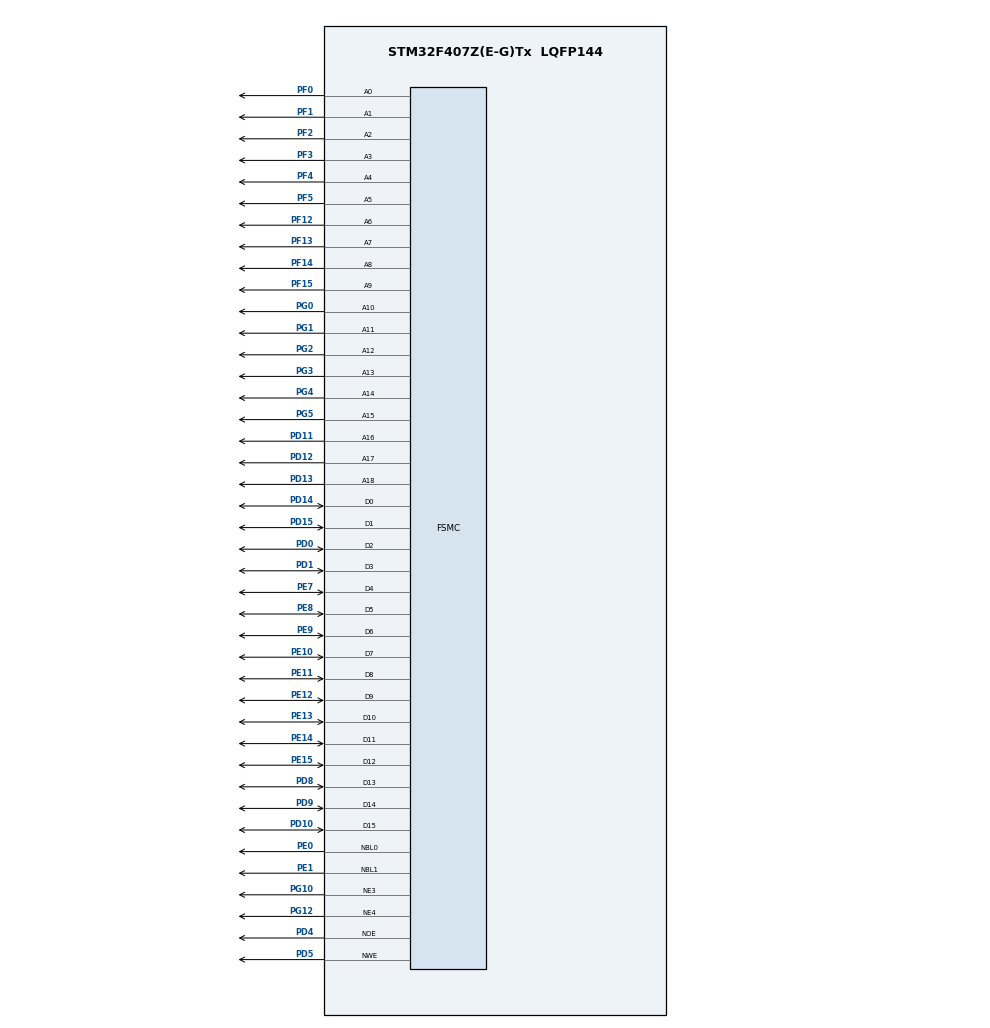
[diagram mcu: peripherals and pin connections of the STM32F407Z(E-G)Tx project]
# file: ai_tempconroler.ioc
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FREERTOS.Tasks01=defaultTask,0,128,StartDefaultTask,Default,NULL,Dynamic,NULL,NULL
FSMC.ExtendedMode1=FSMC_EXTENDED_MODE_DISABLE
FSMC.WriteOperation1=FSMC_WRITE_OPERATION_DISABLE
Mcu.Family=STM32F4
Mcu.Name=STM32F407Z(E-G)Tx
Mcu.Package=LQFP144
NVIC.PriorityGroup=NVIC_PRIORITYGROUP_4
NVIC.TIM1_UP_TIM10_IRQn=true\:15\:0\:false\:false\:true\:false\:false\:true\:true
NVIC.TimeBase=TIM1_UP_TIM10_IRQn
NVIC.TimeBaseIP=TIM1
PC14-OSC32_IN.Mode=LSE-External-Oscillator
PC14-OSC32_IN.Signal=RCC_OSC32_IN
PC15-OSC32_OUT.Mode=LSE-External-Oscillator
PC15-OSC32_OUT.Signal=RCC_OSC32_OUT
PD0.Signal=FSMC_D2_DA2
PD1.Signal=FSMC_D3_DA3
PD10.Signal=FSMC_D15_DA15
PD11.Signal=FSMC_A16_CLE
PD12.Signal=FSMC_A17_ALE
PD13.Signal=FSMC_A18
PD14.Signal=FSMC_D0_DA0
PD15.Signal=FSMC_D1_DA1
PD4.Signal=FSMC_NOE
PD5.Signal=FSMC_NWE
PD8.Signal=FSMC_D13_DA13
PD9.Signal=FSMC_D14_DA14
PE0.Signal=FSMC_NBL0
PE1.Signal=FSMC_NBL1
PE10.Signal=FSMC_D7_DA7
PE11.Signal=FSMC_D8_DA8
PE12.Signal=FSMC_D9_DA9
PE13.Signal=FSMC_D10_DA10
PE14.Signal=FSMC_D11_DA11
PE15.Signal=FSMC_D12_DA12
PE7.Signal=FSMC_D4_DA4
PE8.Signal=FSMC_D5_DA5
PE9.Signal=FSMC_D6_DA6
PF0.Signal=FSMC_A0
PF1.Signal=FSMC_A1
PF12.Signal=FSMC_A6
PF13.Signal=FSMC_A7
PF14.Signal=FSMC_A8
PF15.Signal=FSMC_A9
PF2.Signal=FSMC_A2
PF3.Signal=FSMC_A3
PF4.Signal=FSMC_A4
PF5.Signal=FSMC_A5
PG0.Signal=FSMC_A10
PG1.Signal=FSMC_A11
PG10.Mode=NorPsramChipSelect3_1
PG10.Signal=FSMC_NE3
PG12.Mode=NorPsramChipSelect4_2
PG12.Signal=FSMC_NE4
PG2.Signal=FSMC_A12
PG3.Signal=FSMC_A13
PG4.Signal=FSMC_A14
PG5.Signal=FSMC_A15
PH0-OSC_IN.Mode=HSE-External-Oscillator
PH0-OSC_IN.Signal=RCC_OSC_IN
PH1-OSC_OUT.Mode=HSE-External-Oscillator
PH1-OSC_OUT.Signal=RCC_OSC_OUT
ProjectManager.HeapSize=0x200
ProjectManager.StackSize=0x400
ProjectManager.TargetToolchain=MDK-ARM V5.32
RCC.48MHZClocksFreq_Value=84000000
RCC.AHBFreq_Value=168000000
RCC.APB1CLKDivider=RCC_HCLK_DIV4
RCC.APB1Freq_Value=42000000
RCC.APB1TimFreq_Value=84000000
RCC.APB2CLKDivider=RCC_HCLK_DIV2
RCC.APB2Freq_Value=84000000
RCC.APB2TimFreq_Value=168000000
RCC.CortexFreq_Value=168000000
RCC.HCLKFreq_Value=168000000
RCC.HSE_VALUE=25000000
RCC.HSI_VALUE=16000000
RCC.PLLM=8
RCC.PLLN=168
RCC.SYSCLKFreq_VALUE=168000000
RCC.SYSCLKSource=RCC_SYSCLKSOURCE_PLLCLK
RCC.VCOOutputFreq_Value=336000000
SH.FSMC_A0.0=FSMC_A0,19b-a1
SH.FSMC_A1.0=FSMC_A1,19b-a1
SH.FSMC_A10.0=FSMC_A10,19b-a1
SH.FSMC_A11.0=FSMC_A11,19b-a1
SH.FSMC_A12.0=FSMC_A12,19b-a1
SH.FSMC_A12.1=FSMC_A12,A12_2
SH.FSMC_A13.0=FSMC_A13,19b-a1
SH.FSMC_A14.0=FSMC_A14,19b-a1
SH.FSMC_A15.0=FSMC_A15,19b-a1
SH.FSMC_A16_CLE.0=FSMC_A16,19b-a1
SH.FSMC_A17_ALE.0=FSMC_A17,19b-a1
SH.FSMC_A18.0=FSMC_A18,19b-a1
SH.FSMC_A2.0=FSMC_A2,19b-a1
SH.FSMC_A3.0=FSMC_A3,19b-a1
SH.FSMC_A4.0=FSMC_A4,19b-a1
SH.FSMC_A5.0=FSMC_A5,19b-a1
SH.FSMC_A6.0=FSMC_A6,19b-a1
SH.FSMC_A7.0=FSMC_A7,19b-a1
SH.FSMC_A8.0=FSMC_A8,19b-a1
SH.FSMC_A9.0=FSMC_A9,19b-a1
SH.FSMC_D0_DA0.0=FSMC_D0,16b-d1
SH.FSMC_D0_DA0.1=FSMC_D0,16b-d2
SH.FSMC_D10_DA10.0=FSMC_D10,16b-d1
SH.FSMC_D10_DA10.1=FSMC_D10,16b-d2
SH.FSMC_D11_DA11.0=FSMC_D11,16b-d1
SH.FSMC_D11_DA11.1=FSMC_D11,16b-d2
SH.FSMC_D12_DA12.0=FSMC_D12,16b-d1
SH.FSMC_D12_DA12.1=FSMC_D12,16b-d2
SH.FSMC_D13_DA13.0=FSMC_D13,16b-d1
SH.FSMC_D13_DA13.1=FSMC_D13,16b-d2
SH.FSMC_D14_DA14.0=FSMC_D14,16b-d1
SH.FSMC_D14_DA14.1=FSMC_D14,16b-d2
SH.FSMC_D15_DA15.0=FSMC_D15,16b-d1
SH.FSMC_D15_DA15.1=FSMC_D15,16b-d2
SH.FSMC_D1_DA1.0=FSMC_D1,16b-d1
SH.FSMC_D1_DA1.1=FSMC_D1,16b-d2
SH.FSMC_D2_DA2.0=FSMC_D2,16b-d1
SH.FSMC_D2_DA2.1=FSMC_D2,16b-d2
SH.FSMC_D3_DA3.0=FSMC_D3,16b-d1
SH.FSMC_D3_DA3.1=FSMC_D3,16b-d2
SH.FSMC_D4_DA4.0=FSMC_D4,16b-d1
SH.FSMC_D4_DA4.1=FSMC_D4,16b-d2
SH.FSMC_D5_DA5.0=FSMC_D5,16b-d1
SH.FSMC_D5_DA5.1=FSMC_D5,16b-d2
SH.FSMC_D6_DA6.0=FSMC_D6,16b-d1
SH.FSMC_D6_DA6.1=FSMC_D6,16b-d2
SH.FSMC_D7_DA7.0=FSMC_D7,16b-d1
SH.FSMC_D7_DA7.1=FSMC_D7,16b-d2
SH.FSMC_D8_DA8.0=FSMC_D8,16b-d1
SH.FSMC_D8_DA8.1=FSMC_D8,16b-d2
SH.FSMC_D9_DA9.0=FSMC_D9,16b-d1
SH.FSMC_D9_DA9.1=FSMC_D9,16b-d2
SH.FSMC_NBL0.0=FSMC_NBL0,2ByteEnable1
SH.FSMC_NBL1.0=FSMC_NBL1,2ByteEnable1
SH.FSMC_NOE.0=FSMC_NOE,Sram1
SH.FSMC_NOE.1=FSMC_NOE,Lcd2
SH.FSMC_NWE.0=FSMC_NWE,Sram1
SH.FSMC_NWE.1=FSMC_NWE,Lcd2
VP_FATFS_VS_SRAM.Mode=SRAM
VP_FREERTOS_VS_CMSIS_V1.Mode=CMSIS_V1
VP_LIBJPEG_VS_JPEGLIB.Mode=Enabled
VP_SYS_VS_tim1.Mode=TIM1
board=custom

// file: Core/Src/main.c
/* USER CODE BEGIN Header */
/**
  ******************************************************************************
  * @file           : main.c
  * @brief          : Main program body
  ******************************************************************************
  * @attention
  *
  * Copyright (c) 2026 STMicroelectronics.
  * All rights reserved.
  *
  * This software is licensed under terms that can be found in the LICENSE file
  * in the root directory of this software component.
  * If no LICENSE file comes with this software, it is provided AS-IS.
  *
  ******************************************************************************
  */
/* USER CODE END Header */
#include "main.h"
#include "cmsis_os.h"
#include "fatfs.h"
#include "libjpeg.h"
#include "gpio.h"
#include "fsmc.h"

/* USER CODE BEGIN Includes */
#ifdef ILI9341_SELF_TEST
#include "../../Tests/BSP/ili9341_self_test.h"
#endif
#ifdef LVGL_MINI_TEST
#include "../../Tests/LVGL/lvgl_mini_test.h"
#endif
#include "lvgl.h"
/* USER CODE END Includes */

/* USER CODE BEGIN PV */
extern volatile uint32_t g_boot_stage;

/* USER CODE END PV */

void SystemClock_Config(void);
void MX_FREERTOS_Init(void);

int main(void)
{

  /* MCU Configuration--------------------------------------------------------*/

  /* Reset of all peripherals, Initializes the Flash interface and the Systick. */
  HAL_Init();

  /* Configure the system clock */
  SystemClock_Config();

  /* Initialize all configured peripherals */
  MX_GPIO_Init();
  MX_FSMC_Init();
  MX_FATFS_Init();
  MX_LIBJPEG_Init();
  /* USER CODE BEGIN 2 */
#ifdef ILI9341_SELF_TEST
  ili9341_self_test();
#endif
#ifdef LVGL_MINI_TEST
	lvgl_mini_test();
#endif
  /* USER CODE END 2 */

  /* Call init function for freertos objects (in cmsis_os2.c) */
  MX_FREERTOS_Init();
  g_boot_stage = 0x10U;

  /* Start scheduler */
  osKernelStart();
  g_boot_stage = 0x11U;

  /* We should never get here as control is now taken by the scheduler */

  /* Infinite loop */
  while (1)
  {

  }
}

void SystemClock_Config(void)
{
  RCC_OscInitTypeDef RCC_OscInitStruct = {0};
  RCC_ClkInitTypeDef RCC_ClkInitStruct = {0};

  /** Configure the main internal regulator output voltage
  */
  __HAL_RCC_PWR_CLK_ENABLE();
  __HAL_PWR_VOLTAGESCALING_CONFIG(PWR_REGULATOR_VOLTAGE_SCALE1);

  /** Initializes the RCC Oscillators according to the specified parameters
  * in the RCC_OscInitTypeDef structure.
  */
  RCC_OscInitStruct.OscillatorType = RCC_OSCILLATORTYPE_HSE;
  RCC_OscInitStruct.HSEState = RCC_HSE_ON;
  RCC_OscInitStruct.PLL.PLLState = RCC_PLL_ON;
  RCC_OscInitStruct.PLL.PLLSource = RCC_PLLSOURCE_HSE;
  RCC_OscInitStruct.PLL.PLLM = 8;
  RCC_OscInitStruct.PLL.PLLN = 336;
  RCC_OscInitStruct.PLL.PLLP = RCC_PLLP_DIV2;
  RCC_OscInitStruct.PLL.PLLQ = 7;
  if (HAL_RCC_OscConfig(&RCC_OscInitStruct) != HAL_OK)
  {
    Error_Handler();
  }

  /** Initializes the CPU, AHB and APB buses clocks
  */
  RCC_ClkInitStruct.ClockType = RCC_CLOCKTYPE_HCLK|RCC_CLOCKTYPE_SYSCLK
                              |RCC_CLOCKTYPE_PCLK1|RCC_CLOCKTYPE_PCLK2;
  RCC_ClkInitStruct.SYSCLKSource = RCC_SYSCLKSOURCE_PLLCLK;
  RCC_ClkInitStruct.AHBCLKDivider = RCC_SYSCLK_DIV1;
  RCC_ClkInitStruct.APB1CLKDivider = RCC_HCLK_DIV4;
  RCC_ClkInitStruct.APB2CLKDivider = RCC_HCLK_DIV2;

  if (HAL_RCC_ClockConfig(&RCC_ClkInitStruct, FLASH_LATENCY_5) != HAL_OK)
  {
    Error_Handler();
  }
}

void HAL_TIM_PeriodElapsedCallback(TIM_HandleTypeDef *htim)
{
  if (htim->Instance == TIM1)
  {
    HAL_IncTick();
  }
}

void Error_Handler(void)
{
  /* USER CODE BEGIN Error_Handler_Debug */
  /* User can add his own implementation to report the HAL error return state */
  g_boot_stage = 0xE0U;
  __disable_irq();
  while (1)
  {
  }
  /* USER CODE END Error_Handler_Debug */
}

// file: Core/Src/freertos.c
/* USER CODE BEGIN Header */
/**
  ******************************************************************************
  * File Name          : freertos.c
  * Description        : Code for freertos applications
  ******************************************************************************
  * @attention
  *
  * Copyright (c) 2026 STMicroelectronics.
  * All rights reserved.
  *
  * This software is licensed under terms that can be found in the LICENSE file
  * in the root directory of this software component.
  * If no LICENSE file comes with this software, it is provided AS-IS.
  *
  ******************************************************************************
  */
/* USER CODE END Header */

#include "FreeRTOS.h"
#include "task.h"
#include "main.h"
#include "cmsis_os.h"

/* USER CODE BEGIN Includes */
#include "tianji_ui.h"
#include "tianji_dial.h"
#include "display_drv.h"
#include "touch_drv.h"
#include "lvgl.h"
#include "hil_telemetry.h"

/* USER CODE END Includes */

/* USER CODE BEGIN Variables */
static tianji_ui_t *g_ui = NULL;
volatile uint32_t g_boot_stage = 0U;
volatile uint32_t g_diag_assert_count = 0U;
volatile uint32_t g_diag_hal_tick_last = 0U;
volatile uint32_t g_diag_rtos_tick_last = 0U;
volatile uint32_t g_diag_primask_last = 0U;
volatile uint32_t g_diag_basepri_last = 0U;

/* USER CODE END Variables */
osThreadId defaultTaskHandle;
osThreadId hilTelemetryTaskHandle;

void StartDefaultTask(void const * argument);
void StartHILTelemetryTask(void const * argument);

void MX_FREERTOS_Init(void); /* (MISRA C 2004 rule 8.1) */

/* GetIdleTaskMemory prototype (linked to static allocation support) */
void vApplicationGetIdleTaskMemory( StaticTask_t **ppxIdleTaskTCBBuffer, StackType_t **ppxIdleTaskStackBuffer, uint32_t *pulIdleTaskStackSize );

/* USER CODE BEGIN GET_IDLE_TASK_MEMORY */
static StaticTask_t xIdleTaskTCBBuffer;
static StackType_t xIdleStack[configMINIMAL_STACK_SIZE];

void vApplicationGetIdleTaskMemory( StaticTask_t **ppxIdleTaskTCBBuffer, StackType_t **ppxIdleTaskStackBuffer, uint32_t *pulIdleTaskStackSize )
{
  *ppxIdleTaskTCBBuffer = &xIdleTaskTCBBuffer;
  *ppxIdleTaskStackBuffer = &xIdleStack[0];
  *pulIdleTaskStackSize = configMINIMAL_STACK_SIZE;
  /* place for user code */
}

/* USER CODE END GET_IDLE_TASK_MEMORY */

void MX_FREERTOS_Init(void) {

  /* Create the thread(s) */
  /* definition and creation of defaultTask */
  osThreadDef(defaultTask, StartDefaultTask, osPriorityNormal, 0, 4096);
  defaultTaskHandle = osThreadCreate(osThread(defaultTask), NULL);

  /* USER CODE BEGIN RTOS_THREADS */
  /* HIL Telemetry task — sends JSON frames over UART1 at 100ms intervals */
  osThreadDef(hilTelemetryTask, StartHILTelemetryTask, osPriorityLow, 0, 1024);
  hilTelemetryTaskHandle = osThreadCreate(osThread(hilTelemetryTask), NULL);
  /* USER CODE END RTOS_THREADS */

}

void StartDefaultTask(void const * argument)
{
  /* USER CODE BEGIN StartDefaultTask */
  uint32_t last_lvgl_tick = HAL_GetTick();
  uint32_t last_status_tick = HAL_GetTick();

  (void)argument;

  g_boot_stage = 0x20U;

#ifndef LVGL_MINI_TEST
  lv_init();
  g_boot_stage = 0x21U;

  if (display_drv_init() != 0) {
    Error_Handler();
  }
#endif
  g_boot_stage = 0x22U;

  if (touch_drv_init() != 0) {
    Error_Handler();
  }
  g_boot_stage = 0x23U;

  g_ui = tianji_ui_init();
  if (g_ui == NULL) {
    Error_Handler();
  }
  g_boot_stage = 0x24U;

  display_drv_set_backlight(85);
  g_boot_stage = 0x25U;

  /* Initialize HIL telemetry */
  g_boot_stage = 0x260U;
  HIL_Telemetry_Init();
  g_boot_stage = 0x261U;
  HIL_Telemetry_SetChannel(HIL_CH_BOOT_STAGE, 0x25);
  g_boot_stage = 0x262U;

  g_boot_stage = 0x26U;

  /* Infinite loop */
  for(;;)
  {
    g_boot_stage = 0x263U;
    uint32_t now = HAL_GetTick();

    g_diag_hal_tick_last = now;
    g_diag_rtos_tick_last = xTaskGetTickCount();
    g_diag_primask_last = __get_PRIMASK();
    g_diag_basepri_last = __get_BASEPRI();
    g_boot_stage = 0x264U;

    if ((now - last_lvgl_tick) >= 5U) {
      g_boot_stage = 0x265U;
      last_lvgl_tick = now;
      lv_timer_handler();
      g_boot_stage = 0x266U;
    }

    if ((g_ui != NULL) && ((now - last_status_tick) >= 200U)) {
      int16_t dial_temp;
      g_boot_stage = 0x267U;
      last_status_tick = now;

      dial_temp = tianji_ui_get_temp(g_ui);
      if (dial_temp != g_ui->current_temp) {
        g_ui->current_temp = dial_temp;
        tianji_ui_update_status(g_ui);
      }
      /* Update HIL telemetry channels */
      HIL_Telemetry_SetChannel(HIL_CH_TARGET_TEMP, (int32_t)dial_temp * 10);
      HIL_Telemetry_SetChannel(HIL_CH_CURRENT_TEMP, (int32_t)g_ui->current_temp * 10);
      HIL_Telemetry_SetChannel(HIL_CH_HEAP_FREE, (int32_t)xPortGetFreeHeapSize());
      g_boot_stage = 0x268U;
    }

    g_boot_stage = 0x27U;

    g_boot_stage = 0x271U;
    osDelay(1);
    g_boot_stage = 0x272U;
  }
  /* USER CODE END StartDefaultTask */
}

/* USER CODE BEGIN Application */

/**
  * @brief  HIL Telemetry task — sends JSON frames at 100ms intervals
  * @param  argument: Not used
  */
void StartHILTelemetryTask(void const * argument)
{
  (void)argument;
  TickType_t xLastWakeTime = xTaskGetTickCount();
  const TickType_t xPeriod = pdMS_TO_TICKS(100);

  for (;;)
  {
    g_boot_stage = 0x280U;
    HIL_Telemetry_SendFrame();
    g_boot_stage = 0x281U;
    vTaskDelayUntil(&xLastWakeTime, xPeriod);
  }
}

/* USER CODE END Application */
